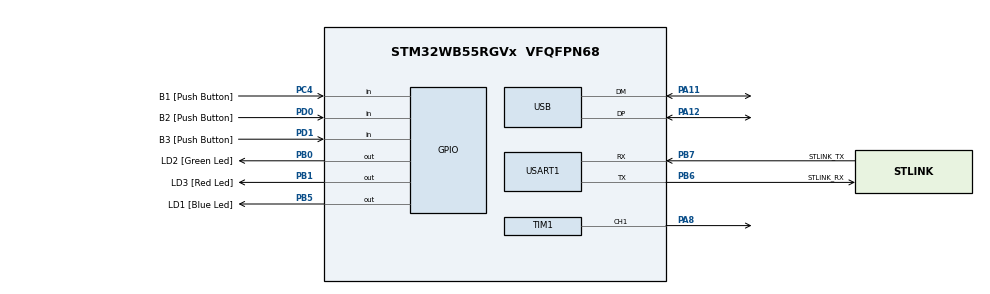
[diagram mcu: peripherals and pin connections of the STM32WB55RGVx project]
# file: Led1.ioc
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Dma.Request0=TIM1_CH1
Dma.TIM1_CH1.0.Direction=DMA_MEMORY_TO_PERIPH
Dma.TIM1_CH1.0.EventEnable=DISABLE
Dma.TIM1_CH1.0.Instance=DMA1_Channel1
Dma.TIM1_CH1.0.MemDataAlignment=DMA_MDATAALIGN_HALFWORD
Dma.TIM1_CH1.0.MemInc=DMA_MINC_ENABLE
Dma.TIM1_CH1.0.Mode=DMA_NORMAL
Dma.TIM1_CH1.0.PeriphDataAlignment=DMA_PDATAALIGN_HALFWORD
Dma.TIM1_CH1.0.PeriphInc=DMA_PINC_DISABLE
Dma.TIM1_CH1.0.Polarity=HAL_DMAMUX_REQ_GEN_RISING
Dma.TIM1_CH1.0.Priority=DMA_PRIORITY_LOW
Dma.TIM1_CH1.0.RequestNumber=1
Dma.TIM1_CH1.0.SignalID=NONE
Dma.TIM1_CH1.0.SyncEnable=DISABLE
Dma.TIM1_CH1.0.SyncPolarity=HAL_DMAMUX_SYNC_NO_EVENT
Dma.TIM1_CH1.0.SyncRequestNumber=1
Dma.TIM1_CH1.0.SyncSignalID=NONE
Mcu.Family=STM32WB
Mcu.Name=STM32WB55RGVx
Mcu.Package=VFQFPN68
NVIC.DMA1_Channel1_IRQn=true\:0\:0\:false\:false\:true\:false\:true\:true
NVIC.PriorityGroup=NVIC_PRIORITYGROUP_4
OSC_IN.Mode=HSE-External-Oscillator
OSC_IN.Signal=RCC_OSC_IN
OSC_OUT.Mode=HSE-External-Oscillator
OSC_OUT.Signal=RCC_OSC_OUT
PA11.Mode=Device
PA11.Signal=USB_DM
PA12.Mode=Device
PA12.Signal=USB_DP
PA13.GPIO_Label=JTMS
PA13.Mode=Trace_Asynchronous_SW
PA13.Signal=SYS_JTMS-SWDIO
PA14.GPIO_Label=JTCK
PA14.Mode=Trace_Asynchronous_SW
PA14.Signal=SYS_JTCK-SWCLK
PA8.Signal=S_TIM1_CH1
PB0.GPIO_Label=LD2 [Green Led]
PB0.Signal=GPIO_Output
PB1.GPIO_Label=LD3 [Red Led]
PB1.Signal=GPIO_Output
PB3.GPIO_Label=JTDO
PB3.Mode=Trace_Asynchronous_SW
PB3.Signal=SYS_JTDO-SWO
PB5.GPIO_Label=LD1 [Blue Led]
PB5.Signal=GPIO_Output
PB6.GPIO_Label=STLINK_RX
PB6.GPIO_PuPd=GPIO_PULLUP
PB6.Mode=Asynchronous
PB6.Signal=USART1_TX
PB7.GPIO_Label=STLINK_TX
PB7.GPIO_PuPd=GPIO_PULLUP
PB7.Mode=Asynchronous
PB7.Signal=USART1_RX
PC13.Mode=SYS_WakeUp1
PC13.Signal=SYS_WKUP2
PC14-OSC32_IN.Mode=LSE-External-Oscillator
PC14-OSC32_IN.Signal=RCC_OSC32_IN
PC15-OSC32_OUT.Mode=LSE-External-Oscillator
PC15-OSC32_OUT.Signal=RCC_OSC32_OUT
PC4.GPIO_Label=B1 [Push Button]
PC4.Signal=GPIO_Input
PD0.GPIO_Label=B2 [Push Button]
PD0.Signal=GPIO_Input
PD1.GPIO_Label=B3 [Push Button]
PD1.Signal=GPIO_Input
ProjectManager.HeapSize=0x200
ProjectManager.StackSize=0x400
ProjectManager.TargetToolchain=STM32CubeIDE
RCC.ADCFreq_Value=54000000
RCC.AHB2CLKDivider=RCC_SYSCLK_DIV2
RCC.AHBFreq_Value=72000000
RCC.APB1Freq_Value=72000000
RCC.APB1TimFreq_Value=72000000
RCC.APB2CLKDivider=RCC_HCLK_DIV2
RCC.APB2Freq_Value=36000000
RCC.APB2TimFreq_Value=72000000
RCC.APB3Freq_Value=18000000
RCC.Cortex2_Div=SYSTICK_CLKSOURCE_HCLK_DIV8
RCC.CortexFreq_Value=72000000
RCC.HCLKFreq_Value=72000000
RCC.HSEPRES=2
RCC.HSE_VALUE=36000000
RCC.HSI48_VALUE=48000000
RCC.HSI_VALUE=16000000
RCC.PLLM=RCC_PLLM_DIV4
RCC.PLLN=80
RCC.PLLR=RCC_PLLR_DIV5
RCC.PLLSAI1N=24
RCC.PLLSourceVirtual=RCC_PLLSOURCE_HSE
RCC.SMPSCLockSelectionVirtual=RCC_SMPSCLKSOURCE_HSI
RCC.SMPSCLockSelectionVirtualVirtual=RCC_SMPSCLKSOURCE_HSI
RCC.SMPSDivider=1
RCC.SYSCLKFreq_VALUE=72000000
RCC.SYSCLKSource=RCC_SYSCLKSOURCE_PLLCLK
RCC.USBFreq_Value=54000000
RCC.VCOOutputFreq_Value=360000000
SH.S_TIM1_CH1.0=TIM1_CH1,PWM Generation1 CH1
TIM1.Channel-PWM\ Generation1\ CH1=TIM_CHANNEL_1
TIM1.Period=72-1
USART1.VirtualMode-Asynchronous=VM_ASYNC
USART1.WordLength=WORDLENGTH_7B
VP_MEMORYMAP_VS_MEMORYMAP.Mode=CurAppReg
VP_TIM1_VS_ClockSourceINT.Mode=Internal
board=NUCLEO-WB55RG

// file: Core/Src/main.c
/* USER CODE BEGIN Header */
/**
  ******************************************************************************
  * @file           : main.c
  * @brief          : Main program body
  ******************************************************************************
  * @attention
  *
  * Copyright (c) 2024 STMicroelectronics.
  * All rights reserved.
  *
  * This software is licensed under terms that can be found in the LICENSE file
  * in the root directory of this software component.
  * If no LICENSE file comes with this software, it is provided AS-IS.
  *
  ******************************************************************************
  */
/* USER CODE END Header */
#include "main.h"
#include <math.h>
#include "ws2812-spi.h"

/* USER CODE BEGIN PD */
#define MAX_LED 8
#define USE_BRIGHTNESS 1

uint8_t LED_Data[MAX_LED][4];
uint8_t LED_Mod[MAX_LED][4];  // for brightness

/* USER CODE END PD */

TIM_HandleTypeDef htim1;
DMA_HandleTypeDef hdma_tim1_ch1;

UART_HandleTypeDef huart1;

PCD_HandleTypeDef hpcd_USB_FS;

void SystemClock_Config(void);
void PeriphCommonClock_Config(void);
static void MX_GPIO_Init(void);
static void MX_DMA_Init(void);
static void MX_USART1_UART_Init(void);
static void MX_USB_PCD_Init(void);
static void MX_TIM1_Init(void);

/* USER CODE BEGIN 0 */

void HAL_TIM_PWM_PulseFinishedCallback(TIM_HandleTypeDef *htim)
{
	volatile int datasentflag = 0;
	HAL_TIM_PWM_Stop_DMA(&htim1, TIM_CHANNEL_1);
	datasentflag=1;
}

void Set_LED (int LEDnum, int Red, int Green, int Blue)
{
	LED_Data[LEDnum][0] = LEDnum;
	LED_Data[LEDnum][1] = Green;
	LED_Data[LEDnum][2] = Red;
	LED_Data[LEDnum][3] = Blue;
}

#define PI 3.14159265

void Set_Brightness (int brightness)  // 0-45
{
#if USE_BRIGHTNESS

	if (brightness > 45) brightness = 45;
	for (int i=0; i<MAX_LED; i++)
	{
		LED_Mod[i][0] = LED_Data[i][0];
		for (int j=1; j<4; j++)
		{
			float angle = 90-brightness;  // in degrees
			angle = angle*PI / 180;  // in rad
			LED_Mod[i][j] = (LED_Data[i][j])/(tan(angle));
		}
	}

#endif

}
uint16_t pwmData[(24*MAX_LED)+50];

void WS2812_Send (void)
{
	uint32_t indx=0;
	uint32_t color;
	volatile int datasentflag= 0;

	for (int i= 0; i<MAX_LED; i++)
	{
#if USE_BRIGHTNESS
		color = ((LED_Mod[i][1]<<16) | (LED_Mod[i][2]<<8) | (LED_Mod[i][3]));
#else
		color = ((LED_Data[i][1]<<16) | (LED_Data[i][2]<<8) | (LED_Data[i][3]));
#endif

		for (int i=23; i>=0; i--)
		{
			if (color&(1<<i))
			{
				pwmData[indx] = 60;  // 2/3 of 90
			}

			else pwmData[indx] = 30;  // 1/3 of 90

			indx++;
		}

	}

	for (int i=0; i<50; i++)
	{
		pwmData[indx] = 0;
		indx++;
	}

	HAL_TIM_PWM_Start_DMA(&htim1, TIM_CHANNEL_1, (uint32_t *)pwmData, indx);
	while (!datasentflag){};
	datasentflag = 0;
}

//void DMA1_Channel1_IRQHandler(void)
//{
//    HAL_DMA_IRQHandler(&hdma_spi2_tx);
//    /* USER CODE BEGIN DMA1_Channel1_IRQn 1 */
//    HAL_SPI_Transmit_DMA(&WS2812_SPI_HANDLE, ws2812_buffer, WS2812_BUFFER_SIZE);
//    /* USER CODE END DMA1_Channel1_IRQn 1 */
//}
//void ws2812_init(void) {
//    memset(ws2812_buffer, 0, WS2812_BUFFER_SIZE);
//    HAL_SPI_Transmit_DMA(&WS2812_SPI_HANDLE, ws2812_buffer, WS2812_BUFFER_SIZE);
//}

/* USER CODE END 0 */

int main(void)
{
  /* USER CODE BEGIN 1 */
	 HAL_Init();

	  SystemClock_Config();
	  MX_GPIO_Init();
	  MX_DMA_Init();
	  MX_TIM1_Init();

	  Set_LED(0, 255, 0, 0);
	  Set_LED(1, 0, 255, 0);
	  Set_LED(2, 0, 0, 255);

	  Set_LED(3, 46, 89, 128);

	  Set_LED(4, 156, 233, 100);
	  Set_LED(5, 102, 0, 235);
	  Set_LED(6, 47, 38, 77);

	  Set_LED(7, 255, 200, 0);

	  while (1)
	  {

		  for (int i=0; i<46; i++)
		  {
			  Set_Brightness(i);
			  WS2812_Send();
			  HAL_Delay (50);
		  }

		  for (int i=45; i>=0; i--)
		  {
			  Set_Brightness(i);
			  WS2812_Send();
			  HAL_Delay (50);
		  }
	  }

  /* USER CODE END 1 */

  /* MCU Configuration--------------------------------------------------------*/

  /* Reset of all peripherals, Initializes the Flash interface and the Systick. */
  HAL_Init();

  /* Configure the system clock */
  SystemClock_Config();

/* Configure the peripherals common clocks */
  PeriphCommonClock_Config();

  /* Initialize all configured peripherals */
  MX_GPIO_Init();
  MX_DMA_Init();
  MX_USART1_UART_Init();
  MX_USB_PCD_Init();
  MX_TIM1_Init();

  /* Infinite loop */
  while (1)
  {

  }
}

void SystemClock_Config(void)
{
  RCC_OscInitTypeDef RCC_OscInitStruct = {0};
  RCC_ClkInitTypeDef RCC_ClkInitStruct = {0};

  /** Configure the main internal regulator output voltage
  */
  __HAL_PWR_VOLTAGESCALING_CONFIG(PWR_REGULATOR_VOLTAGE_SCALE1);

  /** Initializes the RCC Oscillators according to the specified parameters
  * in the RCC_OscInitTypeDef structure.
  */
  RCC_OscInitStruct.OscillatorType = RCC_OSCILLATORTYPE_HSI|RCC_OSCILLATORTYPE_HSE;
  RCC_OscInitStruct.HSEState = RCC_HSE_ON;
  RCC_OscInitStruct.HSIState = RCC_HSI_ON;
  RCC_OscInitStruct.HSICalibrationValue = RCC_HSICALIBRATION_DEFAULT;
  RCC_OscInitStruct.PLL.PLLState = RCC_PLL_ON;
  RCC_OscInitStruct.PLL.PLLSource = RCC_PLLSOURCE_HSE;
  RCC_OscInitStruct.PLL.PLLM = RCC_PLLM_DIV4;
  RCC_OscInitStruct.PLL.PLLN = 80;
  RCC_OscInitStruct.PLL.PLLP = RCC_PLLP_DIV2;
  RCC_OscInitStruct.PLL.PLLR = RCC_PLLR_DIV5;
  RCC_OscInitStruct.PLL.PLLQ = RCC_PLLQ_DIV2;
  if (HAL_RCC_OscConfig(&RCC_OscInitStruct) != HAL_OK)
  {
    Error_Handler();
  }

  /** Enable the HSE Prescaler
  */
  __HAL_RCC_HSE_DIV2_ENABLE();

  /** Configure the SYSCLKSource, HCLK, PCLK1 and PCLK2 clocks dividers
  */
  RCC_ClkInitStruct.ClockType = RCC_CLOCKTYPE_HCLK4|RCC_CLOCKTYPE_HCLK2
                              |RCC_CLOCKTYPE_HCLK|RCC_CLOCKTYPE_SYSCLK
                              |RCC_CLOCKTYPE_PCLK1|RCC_CLOCKTYPE_PCLK2;
  RCC_ClkInitStruct.SYSCLKSource = RCC_SYSCLKSOURCE_PLLCLK;
  RCC_ClkInitStruct.AHBCLKDivider = RCC_SYSCLK_DIV1;
  RCC_ClkInitStruct.APB1CLKDivider = RCC_HCLK_DIV1;
  RCC_ClkInitStruct.APB2CLKDivider = RCC_HCLK_DIV2;
  RCC_ClkInitStruct.AHBCLK2Divider = RCC_SYSCLK_DIV2;
  RCC_ClkInitStruct.AHBCLK4Divider = RCC_SYSCLK_DIV1;

  if (HAL_RCC_ClockConfig(&RCC_ClkInitStruct, FLASH_LATENCY_3) != HAL_OK)
  {
    Error_Handler();
  }
}

void PeriphCommonClock_Config(void)
{
  RCC_PeriphCLKInitTypeDef PeriphClkInitStruct = {0};

  /** Initializes the peripherals clock
  */
  PeriphClkInitStruct.PeriphClockSelection = RCC_PERIPHCLK_SMPS;
  PeriphClkInitStruct.SmpsClockSelection = RCC_SMPSCLKSOURCE_HSI;
  PeriphClkInitStruct.SmpsDivSelection = RCC_SMPSCLKDIV_RANGE0;

  if (HAL_RCCEx_PeriphCLKConfig(&PeriphClkInitStruct) != HAL_OK)
  {
    Error_Handler();
  }
}

static void MX_TIM1_Init(void)
{

  TIM_ClockConfigTypeDef sClockSourceConfig = {0};
  TIM_MasterConfigTypeDef sMasterConfig = {0};
  TIM_OC_InitTypeDef sConfigOC = {0};
  TIM_BreakDeadTimeConfigTypeDef sBreakDeadTimeConfig = {0};

  htim1.Instance = TIM1;
  htim1.Init.Prescaler = 0;
  htim1.Init.CounterMode = TIM_COUNTERMODE_UP;
  htim1.Init.Period = 72-1;
  htim1.Init.ClockDivision = TIM_CLOCKDIVISION_DIV1;
  htim1.Init.RepetitionCounter = 0;
  htim1.Init.AutoReloadPreload = TIM_AUTORELOAD_PRELOAD_DISABLE;
  if (HAL_TIM_Base_Init(&htim1) != HAL_OK)
  {
    Error_Handler();
  }
  sClockSourceConfig.ClockSource = TIM_CLOCKSOURCE_INTERNAL;
  if (HAL_TIM_ConfigClockSource(&htim1, &sClockSourceConfig) != HAL_OK)
  {
    Error_Handler();
  }
  if (HAL_TIM_PWM_Init(&htim1) != HAL_OK)
  {
    Error_Handler();
  }
  sMasterConfig.MasterOutputTrigger = TIM_TRGO_RESET;
  sMasterConfig.MasterOutputTrigger2 = TIM_TRGO2_RESET;
  sMasterConfig.MasterSlaveMode = TIM_MASTERSLAVEMODE_DISABLE;
  if (HAL_TIMEx_MasterConfigSynchronization(&htim1, &sMasterConfig) != HAL_OK)
  {
    Error_Handler();
  }
  sConfigOC.OCMode = TIM_OCMODE_PWM1;
  sConfigOC.Pulse = 0;
  sConfigOC.OCPolarity = TIM_OCPOLARITY_HIGH;
  sConfigOC.OCNPolarity = TIM_OCNPOLARITY_HIGH;
  sConfigOC.OCFastMode = TIM_OCFAST_DISABLE;
  sConfigOC.OCIdleState = TIM_OCIDLESTATE_RESET;
  sConfigOC.OCNIdleState = TIM_OCNIDLESTATE_RESET;
  if (HAL_TIM_PWM_ConfigChannel(&htim1, &sConfigOC, TIM_CHANNEL_1) != HAL_OK)
  {
    Error_Handler();
  }
  sBreakDeadTimeConfig.OffStateRunMode = TIM_OSSR_DISABLE;
  sBreakDeadTimeConfig.OffStateIDLEMode = TIM_OSSI_DISABLE;
  sBreakDeadTimeConfig.LockLevel = TIM_LOCKLEVEL_OFF;
  sBreakDeadTimeConfig.DeadTime = 0;
  sBreakDeadTimeConfig.BreakState = TIM_BREAK_DISABLE;
  sBreakDeadTimeConfig.BreakPolarity = TIM_BREAKPOLARITY_HIGH;
  sBreakDeadTimeConfig.BreakFilter = 0;
  sBreakDeadTimeConfig.BreakAFMode = TIM_BREAK_AFMODE_INPUT;
  sBreakDeadTimeConfig.Break2State = TIM_BREAK2_DISABLE;
  sBreakDeadTimeConfig.Break2Polarity = TIM_BREAK2POLARITY_HIGH;
  sBreakDeadTimeConfig.Break2Filter = 0;
  sBreakDeadTimeConfig.Break2AFMode = TIM_BREAK_AFMODE_INPUT;
  sBreakDeadTimeConfig.AutomaticOutput = TIM_AUTOMATICOUTPUT_DISABLE;
  if (HAL_TIMEx_ConfigBreakDeadTime(&htim1, &sBreakDeadTimeConfig) != HAL_OK)
  {
    Error_Handler();
  }
  HAL_TIM_MspPostInit(&htim1);

}

static void MX_USART1_UART_Init(void)
{

  huart1.Instance = USART1;
  huart1.Init.BaudRate = 115200;
  huart1.Init.WordLength = UART_WORDLENGTH_7B;
  huart1.Init.StopBits = UART_STOPBITS_1;
  huart1.Init.Parity = UART_PARITY_NONE;
  huart1.Init.Mode = UART_MODE_TX_RX;
  huart1.Init.HwFlowCtl = UART_HWCONTROL_NONE;
  huart1.Init.OverSampling = UART_OVERSAMPLING_16;
  huart1.Init.OneBitSampling = UART_ONE_BIT_SAMPLE_DISABLE;
  huart1.Init.ClockPrescaler = UART_PRESCALER_DIV1;
  huart1.AdvancedInit.AdvFeatureInit = UART_ADVFEATURE_NO_INIT;
  if (HAL_UART_Init(&huart1) != HAL_OK)
  {
    Error_Handler();
  }
  if (HAL_UARTEx_SetTxFifoThreshold(&huart1, UART_TXFIFO_THRESHOLD_1_8) != HAL_OK)
  {
    Error_Handler();
  }
  if (HAL_UARTEx_SetRxFifoThreshold(&huart1, UART_RXFIFO_THRESHOLD_1_8) != HAL_OK)
  {
    Error_Handler();
  }
  if (HAL_UARTEx_DisableFifoMode(&huart1) != HAL_OK)
  {
    Error_Handler();
  }

}

static void MX_USB_PCD_Init(void)
{

  hpcd_USB_FS.Instance = USB;
  hpcd_USB_FS.Init.dev_endpoints = 8;
  hpcd_USB_FS.Init.speed = PCD_SPEED_FULL;
  hpcd_USB_FS.Init.phy_itface = PCD_PHY_EMBEDDED;
  hpcd_USB_FS.Init.Sof_enable = DISABLE;
  hpcd_USB_FS.Init.low_power_enable = DISABLE;
  hpcd_USB_FS.Init.lpm_enable = DISABLE;
  hpcd_USB_FS.Init.battery_charging_enable = DISABLE;
  if (HAL_PCD_Init(&hpcd_USB_FS) != HAL_OK)
  {
    Error_Handler();
  }

}

static void MX_DMA_Init(void)
{

  /* DMA controller clock enable */
  __HAL_RCC_DMAMUX1_CLK_ENABLE();
  __HAL_RCC_DMA1_CLK_ENABLE();

  /* DMA interrupt init */
  /* DMA1_Channel1_IRQn interrupt configuration */
  HAL_NVIC_SetPriority(DMA1_Channel1_IRQn, 0, 0);
  HAL_NVIC_EnableIRQ(DMA1_Channel1_IRQn);

}

static void MX_GPIO_Init(void)
{
  GPIO_InitTypeDef GPIO_InitStruct = {0};

  /* GPIO Ports Clock Enable */
  __HAL_RCC_GPIOC_CLK_ENABLE();
  __HAL_RCC_GPIOA_CLK_ENABLE();
  __HAL_RCC_GPIOB_CLK_ENABLE();
  __HAL_RCC_GPIOD_CLK_ENABLE();

  /*Configure GPIO pin Output Level */
  HAL_GPIO_WritePin(GPIOB, LD2_Pin|LD3_Pin|LD1_Pin, GPIO_PIN_RESET);

  /*Configure GPIO pin : B1_Pin */
  GPIO_InitStruct.Pin = B1_Pin;
  GPIO_InitStruct.Mode = GPIO_MODE_INPUT;
  GPIO_InitStruct.Pull = GPIO_NOPULL;
  HAL_GPIO_Init(B1_GPIO_Port, &GPIO_InitStruct);

  /*Configure GPIO pins : LD2_Pin LD3_Pin LD1_Pin */
  GPIO_InitStruct.Pin = LD2_Pin|LD3_Pin|LD1_Pin;
  GPIO_InitStruct.Mode = GPIO_MODE_OUTPUT_PP;
  GPIO_InitStruct.Pull = GPIO_NOPULL;
  GPIO_InitStruct.Speed = GPIO_SPEED_FREQ_LOW;
  HAL_GPIO_Init(GPIOB, &GPIO_InitStruct);

  /*Configure GPIO pins : B2_Pin B3_Pin */
  GPIO_InitStruct.Pin = B2_Pin|B3_Pin;
  GPIO_InitStruct.Mode = GPIO_MODE_INPUT;
  GPIO_InitStruct.Pull = GPIO_NOPULL;
  HAL_GPIO_Init(GPIOD, &GPIO_InitStruct);

}

void Error_Handler(void)
{
  __disable_irq();
  while (1)
  {
  }
}
